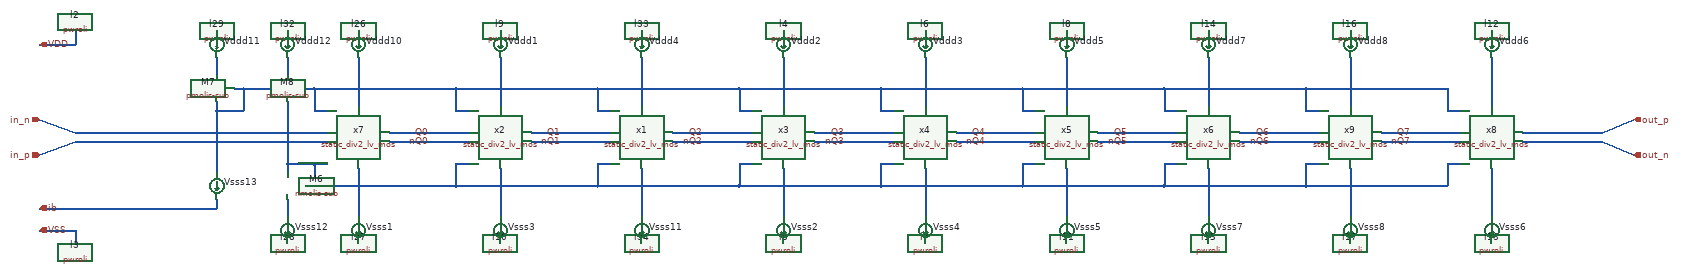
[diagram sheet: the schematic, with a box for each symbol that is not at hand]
v {xschem version=3.4.7RC file_version=1.2
*
* This file is part of XSCHEM,
* a schematic capture and Spice/Vhdl/Verilog netlisting tool for circuit
* simulation.
* Copyright (C) 1998-2023 Stefan Frederik Schippers
*
* This program is free software; you can redistribute it and/or modify
* it under the terms of the GNU General Public License as published by
* the Free Software Foundation; either version 2 of the License, or
* (at your option) any later version.
*
* This program is distributed in the hope that it will be useful,
* but WITHOUT ANY WARRANTY; without even the implied warranty of
* MERCHANTABILITY or FITNESS FOR A PARTICULAR PURPOSE.  See the
* GNU General Public License for more details.
*
* You should have received a copy of the GNU General Public License
* along with this program; if not, write to the Free Software
* Foundation, Inc., 51 Franklin Street, Fifth Floor, Boston, MA 02110-1301 USA
}
G {}
K {}
V {}
S {}
E {}
N 400 -690 480 -690 {
lab=VDD}
N 480 -720 480 -690 {
lab=VDD}
N 400 -270 480 -270 {
lab=VSS}
N 480 -270 480 -240 {
lab=VSS}
N 1440 -660 1440 -550 {lab=VDD}
N 1440 -410 1440 -300 {lab=VSS}
N 1340 -420 1370 -420 {lab=#net1}
N 1340 -540 1370 -540 {lab=ib}
N 1660 -590 1660 -540 {lab=ib}
N 1760 -660 1760 -550 {lab=VDD}
N 1760 -410 1760 -300 {lab=VSS}
N 1660 -420 1690 -420 {lab=#net1}
N 1660 -540 1690 -540 {lab=ib}
N 1340 -590 1660 -590 {lab=ib}
N 1340 -370 1660 -370 {lab=#net1}
N 1660 -420 1660 -370 {lab=#net1}
N 1510 -490 1690 -490 {lab=Q1}
N 1510 -470 1690 -470 {lab=nQ1}
N 1660 -590 1980 -590 {lab=ib}
N 1660 -370 1980 -370 {lab=#net1}
N 1830 -490 2010 -490 {lab=Q2}
N 1830 -470 2010 -470 {lab=nQ2}
N 1340 -420 1340 -370 {lab=#net1}
N 1340 -590 1340 -540 {lab=ib}
N 1120 -660 1120 -550 {lab=VDD}
N 1120 -410 1120 -300 {lab=VSS}
N 1020 -420 1050 -420 {lab=#net1}
N 1020 -540 1050 -540 {lab=ib}
N 960 -340 960 -300 {lab=VSS}
N 800 -660 800 -620 {lab=VDD}
N 1000 -370 1020 -370 {lab=#net1}
N 1020 -420 1020 -370 {lab=#net1}
N 1020 -590 1020 -540 {lab=ib}
N 960 -660 960 -620 {lab=VDD}
N 800 -540 800 -400 {lab=ib}
N 860 -590 1020 -590 {lab=ib}
N 960 -420 960 -400 {lab=#net1}
N 960 -420 1020 -420 {lab=#net1}
N 960 -560 960 -420 {lab=#net1}
N 860 -590 860 -540 {lab=ib}
N 840 -590 860 -590 {lab=ib}
N 800 -540 860 -540 {lab=ib}
N 800 -560 800 -540 {lab=ib}
N 1190 -490 1370 -490 {lab=Q0}
N 1190 -470 1370 -470 {lab=nQ0}
N 1020 -590 1340 -590 {lab=ib}
N 1020 -370 1340 -370 {lab=#net1}
N 2080 -660 2080 -550 {lab=VDD}
N 2080 -410 2080 -300 {lab=VSS}
N 1980 -420 2010 -420 {lab=#net1}
N 1980 -540 2010 -540 {lab=ib}
N 2300 -590 2300 -540 {lab=ib}
N 2400 -660 2400 -550 {lab=VDD}
N 2400 -410 2400 -300 {lab=VSS}
N 2300 -420 2330 -420 {lab=#net1}
N 2300 -540 2330 -540 {lab=ib}
N 1980 -590 2300 -590 {lab=ib}
N 1980 -370 2300 -370 {lab=#net1}
N 2300 -420 2300 -370 {lab=#net1}
N 2150 -490 2330 -490 {lab=Q3}
N 2150 -470 2330 -470 {lab=nQ3}
N 2300 -590 2620 -590 {lab=ib}
N 2300 -370 2620 -370 {lab=#net1}
N 2470 -490 2650 -490 {lab=Q4}
N 2470 -470 2650 -470 {lab=nQ4}
N 1980 -420 1980 -370 {lab=#net1}
N 1980 -590 1980 -540 {lab=ib}
N 2720 -660 2720 -550 {lab=VDD}
N 2720 -410 2720 -300 {lab=VSS}
N 2620 -420 2650 -420 {lab=#net1}
N 2620 -540 2650 -540 {lab=ib}
N 3580 -590 3580 -540 {lab=ib}
N 3680 -660 3680 -550 {lab=VDD}
N 3680 -410 3680 -300 {lab=VSS}
N 3580 -420 3610 -420 {lab=#net1}
N 3580 -540 3610 -540 {lab=ib}
N 2620 -590 2940 -590 {lab=ib}
N 2620 -370 2940 -370 {lab=#net1}
N 3580 -420 3580 -370 {lab=#net1}
N 2790 -490 2970 -490 {lab=Q5}
N 2790 -470 2970 -470 {lab=nQ5}
N 3750 -490 3930 -490 {lab=out_p}
N 3750 -470 3930 -470 {lab=out_n}
N 2620 -420 2620 -370 {lab=#net1}
N 2620 -590 2620 -540 {lab=ib}
N 3930 -470 4000 -440 {lab=out_n}
N 3930 -490 4000 -520 {lab=out_p}
N 480 -490 1050 -490 {lab=in_n}
N 400 -520 480 -490 {lab=in_n}
N 480 -470 1050 -470 {lab=in_p}
N 400 -440 480 -470 {lab=in_p}
N 400 -320 800 -320 {lab=ib}
N 800 -340 800 -320 {lab=ib}
N 3040 -660 3040 -550 {lab=VDD}
N 3040 -410 3040 -300 {lab=VSS}
N 2940 -420 2970 -420 {lab=#net1}
N 2940 -540 2970 -540 {lab=ib}
N 2940 -590 3260 -590 {lab=ib}
N 2940 -370 3260 -370 {lab=#net1}
N 3110 -490 3290 -490 {lab=Q6}
N 3110 -470 3290 -470 {lab=nQ6}
N 2940 -420 2940 -370 {lab=#net1}
N 2940 -590 2940 -540 {lab=ib}
N 3360 -660 3360 -550 {lab=VDD}
N 3360 -410 3360 -300 {lab=VSS}
N 3260 -420 3290 -420 {lab=#net1}
N 3260 -540 3290 -540 {lab=ib}
N 3260 -590 3580 -590 {lab=ib}
N 3260 -370 3580 -370 {lab=#net1}
N 3430 -490 3610 -490 {lab=Q7}
N 3430 -470 3610 -470 {lab=nQ7}
N 3260 -420 3260 -370 {lab=#net1}
N 3260 -590 3260 -540 {lab=ib}
C {title.sym} 160 -30 0 0 {name=l1 author="om"  net_name=true}
C {ipin.sym} 400 -440 0 0 {name=p3 lab=in_p
}
C {ipin.sym} 400 -520 0 0 {name=p1 lab=in_n
}
C {opin.sym} 4000 -520 0 0 {name=p5 lab=out_p

}
C {opin.sym} 4000 -440 0 0 {name=p2 lab=out_n

}
C {iopin.sym} 400 -320 0 1 {name=p13 lab=ib}
C {iopin.sym} 400 -690 0 1 {name=p9 lab=VDD}
C {pwroli.sym} 480 -720 2 0 {name=l2 lab=VDD
}
C {iopin.sym} 400 -270 0 1 {name=p8 lab=VSS

}
C {pwroli.sym} 480 -240 0 0 {name=l3 lab=VSS}
C {launcher.sym} 220 -120 0 0 {name=h2
descr="load OP from TOP"
tclcommand="
	xschem annotate_op $\{netlist_dir\}/[file rootname [file tail [xschem get schname 0]]].raw 0;
	xschem load_raw $\{netlist_dir\}/[file rootname [file tail [xschem get schname 0]]]_dc.raw 0;

"
}
C {launcher.sym} 220 -160 0 0 {name=h1
descr="write LVS netlist"
tclcommand="
	xschem set netlist_type spice
        xschem set format lvs_format
	set last_local_netlist_dir $local_netlist_dir
	set local_netlist_dir 0
	xschem netlist [xschem get current_name].cdl
	set local_netlist_dir $last_local_netlist_dir
        xschem set format \{\}
"
}
C {pwroli.sym} 1440 -720 2 1 {name=l9 lab=VDD
}
C {ammeter.sym} 1440 -690 0 1 {name=Vddd1
savecurrent=true
lvs_ignore=short}
C {pwroli.sym} 1440 -240 0 0 {name=l10 lab=VSS}
C {ammeter.sym} 1440 -270 0 1 {name=Vsss3
savecurrent=true
lvs_ignore=short}
C {lab_pin.sym} 1580 -470 1 1 {name=p6 lab=nQ1  net_name=true}
C {lab_pin.sym} 1580 -490 3 1 {name=p14 lab=Q1  net_name=true}
C {pwroli.sym} 1760 -720 2 1 {name=l33 lab=VDD
}
C {ammeter.sym} 1760 -690 0 1 {name=Vddd4
savecurrent=true
lvs_ignore=short}
C {pwroli.sym} 1760 -240 0 0 {name=l34 lab=VSS}
C {ammeter.sym} 1760 -270 0 1 {name=Vsss11
savecurrent=true
lvs_ignore=short}
C {lab_pin.sym} 1900 -470 1 1 {name=p7 lab=nQ2  net_name=true}
C {lab_pin.sym} 1900 -490 3 1 {name=p10 lab=Q2  net_name=true}
C {pwroli.sym} 1120 -720 2 1 {name=l26 lab=VDD
}
C {ammeter.sym} 1120 -690 0 1 {name=Vddd10
savecurrent=true
lvs_ignore=short}
C {pwroli.sym} 1120 -240 0 0 {name=l27 lab=VSS}
C {ammeter.sym} 1120 -270 0 1 {name=Vsss1
savecurrent=true
lvs_ignore=short}
C {pwroli.sym} 960 -240 0 1 {name=l28 lab=VSS}
C {ammeter.sym} 960 -270 0 1 {name=Vsss12 
savecurrent=true
lvs_ignore=short}
C {pwroli.sym} 800 -720 2 0 {name=l29 lab=VDD
}
C {ammeter.sym} 800 -690 0 0 {name=Vddd11
savecurrent=true
lvs_ignore=short}
C {ngspice_probe.sym} 970 -420 0 0 {name=r4}
C {nmolis-sub.sym} 980 -370 0 1 {name=M6
w=0.15u
l=0.13u
ng=1
m=1
substrate=VSS
model=sg13_lv_nmos
spiceprefix=X
}
C {pmolis-sub.sym} 820 -590 0 1 {name=M7
w=0.3u
l=0.13u
ng=1
m=1
substrate=VDD
model=sg13_lv_pmos
spiceprefix=X
}
C {ngspice_probe.sym} 810 -540 0 0 {name=r5}
C {ammeter.sym} 800 -370 0 1 {name=Vsss13 
savecurrent=true
lvs_ignore=short}
C {pwroli.sym} 960 -720 2 1 {name=l32 lab=VDD
}
C {ammeter.sym} 960 -690 0 1 {name=Vddd12
savecurrent=true
lvs_ignore=short}
C {pmolis-sub.sym} 940 -590 0 0 {name=M8
w=0.3u
l=0.13u
ng=1
m=1
substrate=VDD
model=sg13_lv_pmos
spiceprefix=X
}
C {lab_pin.sym} 1280 -470 1 1 {name=p20 lab=nQ0  net_name=true}
C {lab_pin.sym} 1280 -490 3 1 {name=p21 lab=Q0  net_name=true}
C {pwroli.sym} 2080 -720 2 1 {name=l4 lab=VDD
}
C {ammeter.sym} 2080 -690 0 1 {name=Vddd2
savecurrent=true
lvs_ignore=short}
C {pwroli.sym} 2080 -240 0 0 {name=l5 lab=VSS}
C {ammeter.sym} 2080 -270 0 1 {name=Vsss2
savecurrent=true
lvs_ignore=short}
C {lab_pin.sym} 2220 -470 1 1 {name=p11 lab=nQ3  net_name=true}
C {lab_pin.sym} 2220 -490 3 1 {name=p12 lab=Q3 net_name=true}
C {pwroli.sym} 2400 -720 2 1 {name=l6 lab=VDD
}
C {ammeter.sym} 2400 -690 0 1 {name=Vddd3
savecurrent=true
lvs_ignore=short}
C {pwroli.sym} 2400 -240 0 0 {name=l7 lab=VSS}
C {ammeter.sym} 2400 -270 0 1 {name=Vsss4
savecurrent=true
lvs_ignore=short}
C {lab_pin.sym} 2540 -470 1 1 {name=p15 lab=nQ4  net_name=true}
C {lab_pin.sym} 2540 -490 3 1 {name=p16 lab=Q4  net_name=true}
C {pwroli.sym} 2720 -720 2 1 {name=l8 lab=VDD
}
C {ammeter.sym} 2720 -690 0 1 {name=Vddd5
savecurrent=true
lvs_ignore=short}
C {pwroli.sym} 2720 -240 0 0 {name=l11 lab=VSS}
C {ammeter.sym} 2720 -270 0 1 {name=Vsss5
savecurrent=true
lvs_ignore=short}
C {lab_pin.sym} 2860 -470 1 1 {name=p17 lab=nQ5
  net_name=true}
C {lab_pin.sym} 2860 -490 3 1 {name=p22 lab=Q5
  net_name=true}
C {pwroli.sym} 3680 -720 2 1 {name=l12 lab=VDD
}
C {ammeter.sym} 3680 -690 0 1 {name=Vddd6
savecurrent=true
lvs_ignore=short}
C {pwroli.sym} 3680 -240 0 0 {name=l13 lab=VSS}
C {ammeter.sym} 3680 -270 0 1 {name=Vsss6
savecurrent=true
lvs_ignore=short}
C {lab_pin.sym} 3500 -470 1 1 {name=p23 lab=nQ7  net_name=true}
C {lab_pin.sym} 3500 -490 3 1 {name=p24 lab=Q7  net_name=true}
C {pwroli.sym} 3040 -720 2 1 {name=l14 lab=VDD
}
C {ammeter.sym} 3040 -690 0 1 {name=Vddd7
savecurrent=true
lvs_ignore=short}
C {pwroli.sym} 3040 -240 0 0 {name=l15 lab=VSS}
C {ammeter.sym} 3040 -270 0 1 {name=Vsss7
savecurrent=true
lvs_ignore=short}
C {lab_pin.sym} 3180 -470 1 1 {name=p4 lab=nQ6  net_name=true}
C {lab_pin.sym} 3180 -490 3 1 {name=p25 lab=Q6
  net_name=true}
C {launcher.sym} 130 -210 0 0 {name=h3
descr="write LVS netlist"
tclcommand="
	xschem set netlist_type spice
	set lvs_ignore 1
	set lvs_netlist 1
	set spiceprefix 0
	set last_local_netlist_dir $local_netlist_dir
	set local_netlist_dir 0
	xschem netlist [xschem get current_name].cdl
	set local_netlist_dir $last_local_netlist_dir

"
}
C {tcleval([xschem get current_dirname]/static_div2_lv_mos.sym} 1440 -480 0 0 {name=x2
schematic="tcleval([xschem get current_dirname]/cmos_div2_150nm.sch"
nw=0.15u
nl=0.13u
pw=0.3u
pl=0.13u}
C {tcleval([xschem get current_dirname]/static_div2_lv_mos.sym} 1120 -480 0 0 {name=x7
schematic="tcleval([xschem get current_dirname]/lvl_lvmos.sch"
nw=0.15u
nl=0.13u
pw=0.3u
pl=0.13u}
C {tcleval([xschem get current_dirname]/static_div2_lv_mos.sym} 1760 -480 0 0 {name=x1
schematic="tcleval([xschem get current_dirname]/cmos_div2_150nm.sch"
nw=0.15u
nl=0.13u
pw=0.3u
pl=0.13u}
C {tcleval([xschem get current_dirname]/static_div2_lv_mos.sym} 2080 -480 0 0 {name=x3
schematic="tcleval([xschem get current_dirname]/cmos_div2_150nm.sch"
nw=0.15u
nl=0.13u
pw=0.3u
pl=0.13u}
C {tcleval([xschem get current_dirname]/static_div2_lv_mos.sym} 2400 -480 0 0 {name=x4
schematic="tcleval([xschem get current_dirname]/cmos_div2_150nm.sch"
nw=0.15u
nl=0.13u
pw=0.3u
pl=0.13u}
C {tcleval([xschem get current_dirname]/static_div2_lv_mos.sym} 2720 -480 0 0 {name=x5
schematic="tcleval([xschem get current_dirname]/cmos_div2_150nm.sch"
nw=0.15u
nl=0.13u
pw=0.3u
pl=0.13u}
C {tcleval([xschem get current_dirname]/static_div2_lv_mos.sym} 3040 -480 0 0 {name=x6
schematic="tcleval([xschem get current_dirname]/cmos_div2_150nm.sch"
nw=0.15u
nl=0.13u
pw=0.3u
pl=0.13u}
C {tcleval([xschem get current_dirname]/static_div2_lv_mos.sym} 3680 -480 0 0 {name=x8
schematic="tcleval([xschem get current_dirname]/cmos_div2_150nm.sch"
nw=0.15u
nl=0.13u
pw=0.3u
pl=0.13u}
C {pwroli.sym} 3360 -720 2 1 {name=l16 lab=VDD
}
C {ammeter.sym} 3360 -690 0 1 {name=Vddd8
savecurrent=true
lvs_ignore=short}
C {pwroli.sym} 3360 -240 0 0 {name=l17 lab=VSS}
C {ammeter.sym} 3360 -270 0 1 {name=Vsss8
savecurrent=true
lvs_ignore=short}
C {tcleval([xschem get current_dirname]/static_div2_lv_mos.sym} 3360 -480 0 0 {name=x9
schematic="tcleval([xschem get current_dirname]/cmos_div2_150nm.sch"
nw=0.15u
nl=0.13u
pw=0.3u
pl=0.13u}
